VERSION 5.7 ;
  NOWIREEXTENSIONATPIN ON ;
  DIVIDERCHAR "/" ;
  BUSBITCHARS "[]" ;
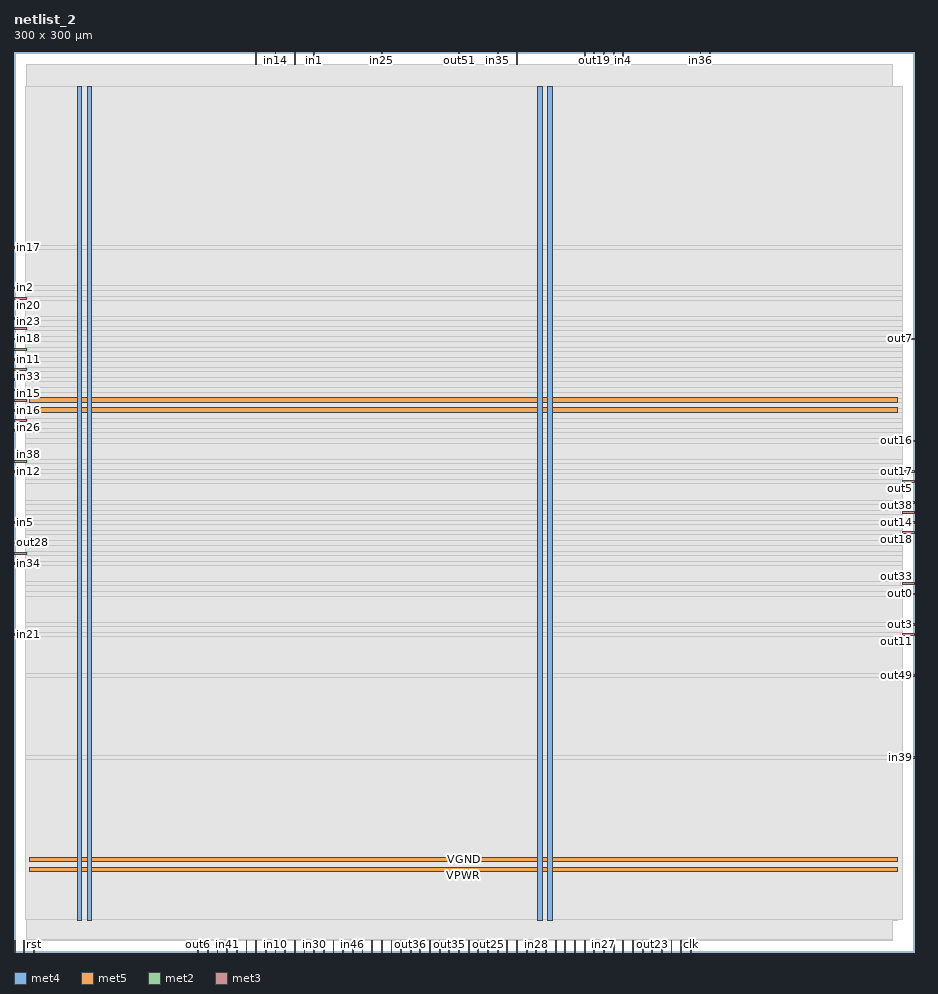
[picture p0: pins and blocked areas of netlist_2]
MACRO netlist_2
  CLASS BLOCK ;
  FOREIGN netlist_2 ;
  ORIGIN 0.000 0.000 ;
  SIZE 300.000 BY 300.000 ;
  PIN VGND
    DIRECTION INOUT ;
    USE GROUND ;
    PORT
      LAYER met4 ;
        RECT 24.340 10.640 25.940 288.560 ;
    END
    PORT
      LAYER met4 ;
        RECT 177.940 10.640 179.540 288.560 ;
    END
    PORT
      LAYER met5 ;
        RECT 5.280 30.030 294.640 31.630 ;
    END
    PORT
      LAYER met5 ;
        RECT 5.280 183.210 294.640 184.810 ;
    END
  END VGND
  PIN VPWR
    DIRECTION INOUT ;
    USE POWER ;
    PORT
      LAYER met4 ;
        RECT 21.040 10.640 22.640 288.560 ;
    END
    PORT
      LAYER met4 ;
        RECT 174.640 10.640 176.240 288.560 ;
    END
    PORT
      LAYER met5 ;
        RECT 5.280 26.730 294.640 28.330 ;
    END
    PORT
      LAYER met5 ;
        RECT 5.280 179.910 294.640 181.510 ;
    END
  END VPWR
  PIN clk
    DIRECTION INPUT ;
    USE SIGNAL ;
    ANTENNAGATEAREA 0.852000 ;
    ANTENNADIFFAREA 0.434700 ;
    PORT
      LAYER met2 ;
        RECT 225.490 0.000 225.770 4.000 ;
    END
  END clk
  PIN in0
    DIRECTION INPUT ;
    USE SIGNAL ;
    ANTENNAGATEAREA 0.213000 ;
    ANTENNADIFFAREA 0.434700 ;
    PORT
      LAYER met2 ;
        RECT 222.270 0.000 222.550 4.000 ;
    END
  END in0
  PIN in1
    DIRECTION INPUT ;
    USE SIGNAL ;
    ANTENNAGATEAREA 0.213000 ;
    ANTENNADIFFAREA 0.434700 ;
    PORT
      LAYER met2 ;
        RECT 99.910 296.000 100.190 300.000 ;
    END
  END in1
  PIN in10
    DIRECTION INPUT ;
    USE SIGNAL ;
    ANTENNAGATEAREA 0.196500 ;
    ANTENNADIFFAREA 0.434700 ;
    PORT
      LAYER met2 ;
        RECT 87.030 0.000 87.310 4.000 ;
    END
  END in10
  PIN in11
    DIRECTION INPUT ;
    USE SIGNAL ;
    ANTENNAGATEAREA 0.196500 ;
    ANTENNADIFFAREA 0.434700 ;
    PORT
      LAYER met3 ;
        RECT 0.000 197.240 4.000 197.840 ;
    END
  END in11
  PIN in12
    DIRECTION INPUT ;
    USE SIGNAL ;
    ANTENNAGATEAREA 0.196500 ;
    ANTENNADIFFAREA 0.434700 ;
    PORT
      LAYER met3 ;
        RECT 0.000 159.840 4.000 160.440 ;
    END
  END in12
  PIN in13
    DIRECTION INPUT ;
    USE SIGNAL ;
    ANTENNAGATEAREA 0.196500 ;
    ANTENNADIFFAREA 0.434700 ;
    PORT
      LAYER met2 ;
        RECT 93.470 296.000 93.750 300.000 ;
    END
  END in13
  PIN in14
    DIRECTION INPUT ;
    USE SIGNAL ;
    ANTENNAGATEAREA 0.213000 ;
    ANTENNADIFFAREA 0.434700 ;
    PORT
      LAYER met2 ;
        RECT 87.030 296.000 87.310 300.000 ;
    END
  END in14
  PIN in15
    DIRECTION INPUT ;
    USE SIGNAL ;
    ANTENNAGATEAREA 0.213000 ;
    ANTENNADIFFAREA 0.434700 ;
    PORT
      LAYER met3 ;
        RECT 0.000 183.640 4.000 184.240 ;
    END
  END in15
  PIN in16
    DIRECTION INPUT ;
    USE SIGNAL ;
    ANTENNAGATEAREA 0.126000 ;
    ANTENNADIFFAREA 0.434700 ;
    PORT
      LAYER met3 ;
        RECT 0.000 180.240 4.000 180.840 ;
    END
  END in16
  PIN in17
    DIRECTION INPUT ;
    USE SIGNAL ;
    ANTENNAGATEAREA 0.213000 ;
    ANTENNADIFFAREA 0.434700 ;
    PORT
      LAYER met3 ;
        RECT 0.000 234.640 4.000 235.240 ;
    END
  END in17
  PIN in18
    DIRECTION INPUT ;
    USE SIGNAL ;
    ANTENNAGATEAREA 0.196500 ;
    ANTENNADIFFAREA 0.434700 ;
    PORT
      LAYER met3 ;
        RECT 0.000 204.040 4.000 204.640 ;
    END
  END in18
  PIN in19
    DIRECTION INPUT ;
    USE SIGNAL ;
    ANTENNAGATEAREA 0.213000 ;
    ANTENNADIFFAREA 0.434700 ;
    PORT
      LAYER met2 ;
        RECT 215.830 0.000 216.110 4.000 ;
    END
  END in19
  PIN in2
    DIRECTION INPUT ;
    USE SIGNAL ;
    ANTENNAGATEAREA 0.213000 ;
    ANTENNADIFFAREA 0.434700 ;
    PORT
      LAYER met3 ;
        RECT 0.000 221.040 4.000 221.640 ;
    END
  END in2
  PIN in20
    DIRECTION INPUT ;
    USE SIGNAL ;
    ANTENNAGATEAREA 0.213000 ;
    ANTENNADIFFAREA 0.434700 ;
    PORT
      LAYER met3 ;
        RECT 0.000 217.640 4.000 218.240 ;
    END
  END in20
  PIN in21
    DIRECTION INPUT ;
    USE SIGNAL ;
    ANTENNAGATEAREA 0.196500 ;
    ANTENNADIFFAREA 0.434700 ;
    PORT
      LAYER met3 ;
        RECT 0.000 105.440 4.000 106.040 ;
    END
  END in21
  PIN in22
    DIRECTION INPUT ;
    USE SIGNAL ;
    ANTENNAGATEAREA 0.196500 ;
    ANTENNADIFFAREA 0.434700 ;
    PORT
      LAYER met2 ;
        RECT 67.710 0.000 67.990 4.000 ;
    END
  END in22
  PIN in23
    DIRECTION INPUT ;
    USE SIGNAL ;
    ANTENNAGATEAREA 0.196500 ;
    ANTENNADIFFAREA 0.434700 ;
    PORT
      LAYER met3 ;
        RECT 0.000 207.440 4.000 208.040 ;
    END
  END in23
  PIN in24
    DIRECTION INPUT ;
    USE SIGNAL ;
    ANTENNAGATEAREA 0.196500 ;
    ANTENNADIFFAREA 0.434700 ;
    PORT
      LAYER met2 ;
        RECT 93.470 0.000 93.750 4.000 ;
    END
  END in24
  PIN in25
    DIRECTION INPUT ;
    USE SIGNAL ;
    ANTENNAGATEAREA 0.196500 ;
    ANTENNADIFFAREA 0.434700 ;
    PORT
      LAYER met2 ;
        RECT 122.450 296.000 122.730 300.000 ;
    END
  END in25
  PIN in26
    DIRECTION INPUT ;
    USE SIGNAL ;
    ANTENNAGATEAREA 0.196500 ;
    ANTENNADIFFAREA 0.434700 ;
    PORT
      LAYER met3 ;
        RECT 0.000 176.840 4.000 177.440 ;
    END
  END in26
  PIN in27
    DIRECTION INPUT ;
    USE SIGNAL ;
    ANTENNAGATEAREA 0.196500 ;
    ANTENNADIFFAREA 0.434700 ;
    PORT
      LAYER met2 ;
        RECT 196.510 0.000 196.790 4.000 ;
    END
  END in27
  PIN in28
    DIRECTION INPUT ;
    USE SIGNAL ;
    ANTENNAGATEAREA 0.196500 ;
    ANTENNADIFFAREA 0.434700 ;
    PORT
      LAYER met2 ;
        RECT 173.970 0.000 174.250 4.000 ;
    END
  END in28
  PIN in29
    DIRECTION INPUT ;
    USE SIGNAL ;
    ANTENNAGATEAREA 0.196500 ;
    ANTENNADIFFAREA 0.434700 ;
    PORT
      LAYER met3 ;
        RECT 0.000 200.640 4.000 201.240 ;
    END
  END in29
  PIN in3
    DIRECTION INPUT ;
    USE SIGNAL ;
    ANTENNAGATEAREA 0.213000 ;
    ANTENNADIFFAREA 0.434700 ;
    PORT
      LAYER met3 ;
        RECT 0.000 210.840 4.000 211.440 ;
    END
  END in3
  PIN in30
    DIRECTION INPUT ;
    USE SIGNAL ;
    ANTENNAGATEAREA 0.196500 ;
    ANTENNADIFFAREA 0.434700 ;
    PORT
      LAYER met2 ;
        RECT 99.910 0.000 100.190 4.000 ;
    END
  END in30
  PIN in31
    DIRECTION INPUT ;
    USE SIGNAL ;
    ANTENNAGATEAREA 0.213000 ;
    ANTENNADIFFAREA 0.434700 ;
    PORT
      LAYER met2 ;
        RECT 90.250 0.000 90.530 4.000 ;
    END
  END in31
  PIN in32
    DIRECTION INPUT ;
    USE SIGNAL ;
    ANTENNAGATEAREA 0.213000 ;
    ANTENNADIFFAREA 0.434700 ;
    PORT
      LAYER met2 ;
        RECT 138.550 0.000 138.830 4.000 ;
    END
  END in32
  PIN in33
    DIRECTION INPUT ;
    USE SIGNAL ;
    ANTENNAGATEAREA 0.196500 ;
    ANTENNADIFFAREA 0.434700 ;
    PORT
      LAYER met3 ;
        RECT 0.000 193.840 4.000 194.440 ;
    END
  END in33
  PIN in34
    DIRECTION INPUT ;
    USE SIGNAL ;
    ANTENNAGATEAREA 0.196500 ;
    ANTENNADIFFAREA 0.434700 ;
    PORT
      LAYER met3 ;
        RECT 0.000 129.240 4.000 129.840 ;
    END
  END in34
  PIN in35
    DIRECTION INPUT ;
    USE SIGNAL ;
    ANTENNAGATEAREA 0.159000 ;
    ANTENNADIFFAREA 0.434700 ;
    PORT
      LAYER met2 ;
        RECT 161.090 296.000 161.370 300.000 ;
    END
  END in35
  PIN in36
    DIRECTION INPUT ;
    USE SIGNAL ;
    ANTENNAGATEAREA 0.196500 ;
    ANTENNADIFFAREA 0.434700 ;
    PORT
      LAYER met2 ;
        RECT 228.710 296.000 228.990 300.000 ;
    END
  END in36
  PIN in37
    DIRECTION INPUT ;
    USE SIGNAL ;
    ANTENNAGATEAREA 0.213000 ;
    ANTENNADIFFAREA 0.434700 ;
    PORT
      LAYER met2 ;
        RECT 83.810 0.000 84.090 4.000 ;
    END
  END in37
  PIN in38
    DIRECTION INPUT ;
    USE SIGNAL ;
    ANTENNAGATEAREA 0.196500 ;
    ANTENNADIFFAREA 0.434700 ;
    PORT
      LAYER met3 ;
        RECT 0.000 163.240 4.000 163.840 ;
    END
  END in38
  PIN in39
    DIRECTION INPUT ;
    USE SIGNAL ;
    ANTENNAGATEAREA 0.426000 ;
    ANTENNADIFFAREA 0.434700 ;
    PORT
      LAYER met3 ;
        RECT 296.000 64.640 300.000 65.240 ;
    END
  END in39
  PIN in4
    DIRECTION INPUT ;
    USE SIGNAL ;
    ANTENNAGATEAREA 0.159000 ;
    ANTENNADIFFAREA 0.434700 ;
    PORT
      LAYER met2 ;
        RECT 202.950 296.000 203.230 300.000 ;
    END
  END in4
  PIN in40
    DIRECTION INPUT ;
    USE SIGNAL ;
    ANTENNAGATEAREA 0.159000 ;
    ANTENNADIFFAREA 0.434700 ;
    PORT
      LAYER met2 ;
        RECT 167.530 0.000 167.810 4.000 ;
    END
  END in40
  PIN in41
    DIRECTION INPUT ;
    USE SIGNAL ;
    ANTENNAGATEAREA 0.196500 ;
    ANTENNADIFFAREA 0.434700 ;
    PORT
      LAYER met2 ;
        RECT 70.930 0.000 71.210 4.000 ;
    END
  END in41
  PIN in42
    DIRECTION INPUT ;
    USE SIGNAL ;
    ANTENNAGATEAREA 0.159000 ;
    ANTENNADIFFAREA 0.434700 ;
    PORT
      LAYER met2 ;
        RECT 109.570 0.000 109.850 4.000 ;
    END
  END in42
  PIN in43
    DIRECTION INPUT ;
    USE SIGNAL ;
    ANTENNAGATEAREA 0.196500 ;
    ANTENNADIFFAREA 0.434700 ;
    PORT
      LAYER met2 ;
        RECT 80.590 0.000 80.870 4.000 ;
    END
  END in43
  PIN in44
    DIRECTION INPUT ;
    USE SIGNAL ;
    ANTENNAGATEAREA 0.196500 ;
    ANTENNADIFFAREA 0.434700 ;
    PORT
      LAYER met2 ;
        RECT 119.230 0.000 119.510 4.000 ;
    END
  END in44
  PIN in45
    DIRECTION INPUT ;
    USE SIGNAL ;
    ANTENNAGATEAREA 0.196500 ;
    ANTENNADIFFAREA 0.434700 ;
    PORT
      LAYER met2 ;
        RECT 103.130 0.000 103.410 4.000 ;
    END
  END in45
  PIN in46
    DIRECTION INPUT ;
    USE SIGNAL ;
    ANTENNAGATEAREA 0.213000 ;
    ANTENNADIFFAREA 0.434700 ;
    PORT
      LAYER met2 ;
        RECT 112.790 0.000 113.070 4.000 ;
    END
  END in46
  PIN in47
    DIRECTION INPUT ;
    USE SIGNAL ;
    ANTENNAGATEAREA 0.213000 ;
    ANTENNADIFFAREA 0.434700 ;
    PORT
      LAYER met2 ;
        RECT 116.010 0.000 116.290 4.000 ;
    END
  END in47
  PIN in48
    DIRECTION INPUT ;
    USE SIGNAL ;
    ANTENNAGATEAREA 0.196500 ;
    ANTENNADIFFAREA 0.434700 ;
    PORT
      LAYER met2 ;
        RECT 77.370 0.000 77.650 4.000 ;
    END
  END in48
  PIN in49
    DIRECTION INPUT ;
    USE SIGNAL ;
    ANTENNAGATEAREA 0.159000 ;
    ANTENNADIFFAREA 0.434700 ;
    PORT
      LAYER met3 ;
        RECT 0.000 132.640 4.000 133.240 ;
    END
  END in49
  PIN in5
    DIRECTION INPUT ;
    USE SIGNAL ;
    ANTENNAGATEAREA 0.159000 ;
    ANTENNADIFFAREA 0.434700 ;
    PORT
      LAYER met3 ;
        RECT 0.000 142.840 4.000 143.440 ;
    END
  END in5
  PIN in50
    DIRECTION INPUT ;
    USE SIGNAL ;
    ANTENNAGATEAREA 0.196500 ;
    ANTENNADIFFAREA 0.434700 ;
    PORT
      LAYER met2 ;
        RECT 74.150 0.000 74.430 4.000 ;
    END
  END in50
  PIN in51
    DIRECTION INPUT ;
    USE SIGNAL ;
    ANTENNAGATEAREA 0.196500 ;
    ANTENNADIFFAREA 0.434700 ;
    PORT
      LAYER met2 ;
        RECT 106.350 0.000 106.630 4.000 ;
    END
  END in51
  PIN in6
    DIRECTION INPUT ;
    USE SIGNAL ;
    ANTENNAGATEAREA 0.159000 ;
    ANTENNADIFFAREA 0.434700 ;
    PORT
      LAYER met3 ;
        RECT 0.000 173.440 4.000 174.040 ;
    END
  END in6
  PIN in7
    DIRECTION INPUT ;
    USE SIGNAL ;
    ANTENNAGATEAREA 0.196500 ;
    ANTENNADIFFAREA 0.434700 ;
    PORT
      LAYER met2 ;
        RECT 80.590 296.000 80.870 300.000 ;
    END
  END in7
  PIN in8
    DIRECTION INPUT ;
    USE SIGNAL ;
    ANTENNAGATEAREA 0.159000 ;
    ANTENNADIFFAREA 0.434700 ;
    PORT
      LAYER met3 ;
        RECT 0.000 190.440 4.000 191.040 ;
    END
  END in8
  PIN in9
    DIRECTION INPUT ;
    USE SIGNAL ;
    ANTENNAGATEAREA 0.213000 ;
    ANTENNADIFFAREA 0.434700 ;
    PORT
      LAYER met3 ;
        RECT 0.000 187.040 4.000 187.640 ;
    END
  END in9
  PIN out0
    DIRECTION OUTPUT ;
    USE SIGNAL ;
    ANTENNADIFFAREA 0.445500 ;
    PORT
      LAYER met3 ;
        RECT 296.000 119.040 300.000 119.640 ;
    END
  END out0
  PIN out1
    DIRECTION OUTPUT ;
    USE SIGNAL ;
    ANTENNADIFFAREA 0.445500 ;
    PORT
      LAYER met2 ;
        RECT 202.950 0.000 203.230 4.000 ;
    END
  END out1
  PIN out10
    DIRECTION OUTPUT ;
    USE SIGNAL ;
    ANTENNADIFFAREA 0.445500 ;
    PORT
      LAYER met2 ;
        RECT 135.330 0.000 135.610 4.000 ;
    END
  END out10
  PIN out11
    DIRECTION OUTPUT ;
    USE SIGNAL ;
    ANTENNADIFFAREA 0.445500 ;
    PORT
      LAYER met3 ;
        RECT 296.000 105.440 300.000 106.040 ;
    END
  END out11
  PIN out12
    DIRECTION OUTPUT ;
    USE SIGNAL ;
    ANTENNADIFFAREA 0.445500 ;
    PORT
      LAYER met3 ;
        RECT 296.000 149.640 300.000 150.240 ;
    END
  END out12
  PIN out13
    DIRECTION OUTPUT ;
    USE SIGNAL ;
    ANTENNADIFFAREA 0.445500 ;
    PORT
      LAYER met2 ;
        RECT 141.770 0.000 142.050 4.000 ;
    END
  END out13
  PIN out14
    DIRECTION OUTPUT ;
    USE SIGNAL ;
    ANTENNADIFFAREA 0.445500 ;
    PORT
      LAYER met3 ;
        RECT 296.000 142.840 300.000 143.440 ;
    END
  END out14
  PIN out15
    DIRECTION OUTPUT ;
    USE SIGNAL ;
    ANTENNADIFFAREA 0.795200 ;
    PORT
      LAYER met2 ;
        RECT 231.930 296.000 232.210 300.000 ;
    END
  END out15
  PIN out16
    DIRECTION OUTPUT ;
    USE SIGNAL ;
    ANTENNADIFFAREA 0.445500 ;
    PORT
      LAYER met3 ;
        RECT 296.000 170.040 300.000 170.640 ;
    END
  END out16
  PIN out17
    DIRECTION OUTPUT ;
    USE SIGNAL ;
    ANTENNADIFFAREA 0.340600 ;
    PORT
      LAYER met3 ;
        RECT 296.000 159.840 300.000 160.440 ;
    END
  END out17
  PIN out18
    DIRECTION OUTPUT ;
    USE SIGNAL ;
    ANTENNADIFFAREA 0.340600 ;
    PORT
      LAYER met3 ;
        RECT 296.000 139.440 300.000 140.040 ;
    END
  END out18
  PIN out19
    DIRECTION OUTPUT ;
    USE SIGNAL ;
    ANTENNADIFFAREA 0.795200 ;
    PORT
      LAYER met2 ;
        RECT 193.290 296.000 193.570 300.000 ;
    END
  END out19
  PIN out2
    DIRECTION OUTPUT ;
    USE SIGNAL ;
    ANTENNADIFFAREA 0.795200 ;
    PORT
      LAYER met2 ;
        RECT 196.510 296.000 196.790 300.000 ;
    END
  END out2
  PIN out20
    DIRECTION OUTPUT ;
    USE SIGNAL ;
    ANTENNADIFFAREA 0.445500 ;
    PORT
      LAYER met2 ;
        RECT 125.670 0.000 125.950 4.000 ;
    END
  END out20
  PIN out21
    DIRECTION OUTPUT ;
    USE SIGNAL ;
    ANTENNADIFFAREA 0.445500 ;
    PORT
      LAYER met2 ;
        RECT 170.750 0.000 171.030 4.000 ;
    END
  END out21
  PIN out22
    DIRECTION OUTPUT ;
    USE SIGNAL ;
    PORT
      LAYER met2 ;
        RECT 0.090 0.000 0.370 4.000 ;
    END
  END out22
  PIN out23
    DIRECTION OUTPUT ;
    USE SIGNAL ;
    ANTENNADIFFAREA 0.445500 ;
    PORT
      LAYER met2 ;
        RECT 212.610 0.000 212.890 4.000 ;
    END
  END out23
  PIN out24
    DIRECTION OUTPUT ;
    USE SIGNAL ;
    ANTENNADIFFAREA 0.795200 ;
    PORT
      LAYER met2 ;
        RECT 199.730 296.000 200.010 300.000 ;
    END
  END out24
  PIN out25
    DIRECTION OUTPUT ;
    USE SIGNAL ;
    ANTENNADIFFAREA 0.445500 ;
    PORT
      LAYER met2 ;
        RECT 157.870 0.000 158.150 4.000 ;
    END
  END out25
  PIN out26
    DIRECTION OUTPUT ;
    USE SIGNAL ;
    ANTENNADIFFAREA 0.795200 ;
    PORT
      LAYER met2 ;
        RECT 190.070 296.000 190.350 300.000 ;
    END
  END out26
  PIN out27
    DIRECTION OUTPUT ;
    USE SIGNAL ;
    ANTENNADIFFAREA 0.340600 ;
    PORT
      LAYER met2 ;
        RECT 206.170 0.000 206.450 4.000 ;
    END
  END out27
  PIN out28
    DIRECTION OUTPUT ;
    USE SIGNAL ;
    ANTENNADIFFAREA 0.445500 ;
    PORT
      LAYER met3 ;
        RECT 0.000 136.040 4.000 136.640 ;
    END
  END out28
  PIN out29
    DIRECTION OUTPUT ;
    USE SIGNAL ;
    ANTENNADIFFAREA 0.445500 ;
    PORT
      LAYER met2 ;
        RECT 64.490 0.000 64.770 4.000 ;
    END
  END out29
  PIN out3
    DIRECTION OUTPUT ;
    USE SIGNAL ;
    ANTENNADIFFAREA 0.445500 ;
    PORT
      LAYER met3 ;
        RECT 296.000 108.840 300.000 109.440 ;
    END
  END out3
  PIN out30
    DIRECTION OUTPUT ;
    USE SIGNAL ;
    ANTENNADIFFAREA 0.445500 ;
    PORT
      LAYER met2 ;
        RECT 96.690 0.000 96.970 4.000 ;
    END
  END out30
  PIN out31
    DIRECTION OUTPUT ;
    USE SIGNAL ;
    ANTENNADIFFAREA 0.445500 ;
    PORT
      LAYER met2 ;
        RECT 148.210 0.000 148.490 4.000 ;
    END
  END out31
  PIN out32
    DIRECTION OUTPUT ;
    USE SIGNAL ;
    ANTENNADIFFAREA 0.445500 ;
    PORT
      LAYER met2 ;
        RECT 183.630 0.000 183.910 4.000 ;
    END
  END out32
  PIN out33
    DIRECTION OUTPUT ;
    USE SIGNAL ;
    ANTENNADIFFAREA 0.445500 ;
    PORT
      LAYER met3 ;
        RECT 296.000 122.440 300.000 123.040 ;
    END
  END out33
  PIN out34
    DIRECTION OUTPUT ;
    USE SIGNAL ;
    ANTENNADIFFAREA 0.445500 ;
    PORT
      LAYER met2 ;
        RECT 128.890 0.000 129.170 4.000 ;
    END
  END out34
  PIN out35
    DIRECTION OUTPUT ;
    USE SIGNAL ;
    ANTENNADIFFAREA 0.445500 ;
    PORT
      LAYER met2 ;
        RECT 144.990 0.000 145.270 4.000 ;
    END
  END out35
  PIN out36
    DIRECTION OUTPUT ;
    USE SIGNAL ;
    ANTENNADIFFAREA 0.445500 ;
    PORT
      LAYER met2 ;
        RECT 132.110 0.000 132.390 4.000 ;
    END
  END out36
  PIN out37
    DIRECTION OUTPUT ;
    USE SIGNAL ;
    ANTENNADIFFAREA 0.445500 ;
    PORT
      LAYER met2 ;
        RECT 180.410 0.000 180.690 4.000 ;
    END
  END out37
  PIN out38
    DIRECTION OUTPUT ;
    USE SIGNAL ;
    ANTENNADIFFAREA 0.445500 ;
    PORT
      LAYER met3 ;
        RECT 296.000 146.240 300.000 146.840 ;
    END
  END out38
  PIN out39
    DIRECTION OUTPUT ;
    USE SIGNAL ;
    ANTENNADIFFAREA 0.445500 ;
    PORT
      LAYER met2 ;
        RECT 193.290 0.000 193.570 4.000 ;
    END
  END out39
  PIN out4
    DIRECTION OUTPUT ;
    USE SIGNAL ;
    ANTENNADIFFAREA 0.445500 ;
    PORT
      LAYER met2 ;
        RECT 154.650 0.000 154.930 4.000 ;
    END
  END out4
  PIN out40
    DIRECTION OUTPUT ;
    USE SIGNAL ;
    ANTENNADIFFAREA 0.445500 ;
    PORT
      LAYER met2 ;
        RECT 186.850 0.000 187.130 4.000 ;
    END
  END out40
  PIN out41
    DIRECTION OUTPUT ;
    USE SIGNAL ;
    ANTENNADIFFAREA 0.445500 ;
    PORT
      LAYER met2 ;
        RECT 151.430 0.000 151.710 4.000 ;
    END
  END out41
  PIN out42
    DIRECTION OUTPUT ;
    USE SIGNAL ;
    ANTENNADIFFAREA 0.340600 ;
    PORT
      LAYER met2 ;
        RECT 167.530 296.000 167.810 300.000 ;
    END
  END out42
  PIN out43
    DIRECTION OUTPUT ;
    USE SIGNAL ;
    ANTENNADIFFAREA 0.445500 ;
    PORT
      LAYER met2 ;
        RECT 122.450 0.000 122.730 4.000 ;
    END
  END out43
  PIN out44
    DIRECTION OUTPUT ;
    USE SIGNAL ;
    ANTENNADIFFAREA 0.445500 ;
    PORT
      LAYER met2 ;
        RECT 177.190 0.000 177.470 4.000 ;
    END
  END out44
  PIN out45
    DIRECTION OUTPUT ;
    USE SIGNAL ;
    PORT
      LAYER met2 ;
        RECT 3.310 0.000 3.590 4.000 ;
    END
  END out45
  PIN out46
    DIRECTION OUTPUT ;
    USE SIGNAL ;
    ANTENNADIFFAREA 0.445500 ;
    PORT
      LAYER met2 ;
        RECT 164.310 0.000 164.590 4.000 ;
    END
  END out46
  PIN out47
    DIRECTION OUTPUT ;
    USE SIGNAL ;
    ANTENNADIFFAREA 0.445500 ;
    PORT
      LAYER met2 ;
        RECT 219.050 0.000 219.330 4.000 ;
    END
  END out47
  PIN out48
    DIRECTION OUTPUT ;
    USE SIGNAL ;
    ANTENNADIFFAREA 0.340600 ;
    PORT
      LAYER met2 ;
        RECT 190.070 0.000 190.350 4.000 ;
    END
  END out48
  PIN out49
    DIRECTION OUTPUT ;
    USE SIGNAL ;
    ANTENNADIFFAREA 0.445500 ;
    PORT
      LAYER met3 ;
        RECT 296.000 91.840 300.000 92.440 ;
    END
  END out49
  PIN out5
    DIRECTION OUTPUT ;
    USE SIGNAL ;
    ANTENNADIFFAREA 0.445500 ;
    PORT
      LAYER met3 ;
        RECT 296.000 156.440 300.000 157.040 ;
    END
  END out5
  PIN out50
    DIRECTION OUTPUT ;
    USE SIGNAL ;
    ANTENNADIFFAREA 0.340600 ;
    PORT
      LAYER met2 ;
        RECT 161.090 0.000 161.370 4.000 ;
    END
  END out50
  PIN out51
    DIRECTION OUTPUT ;
    USE SIGNAL ;
    ANTENNADIFFAREA 0.340600 ;
    PORT
      LAYER met2 ;
        RECT 148.210 296.000 148.490 300.000 ;
    END
  END out51
  PIN out6
    DIRECTION OUTPUT ;
    USE SIGNAL ;
    ANTENNADIFFAREA 0.445500 ;
    PORT
      LAYER met2 ;
        RECT 61.270 0.000 61.550 4.000 ;
    END
  END out6
  PIN out7
    DIRECTION OUTPUT ;
    USE SIGNAL ;
    ANTENNADIFFAREA 0.445500 ;
    PORT
      LAYER met3 ;
        RECT 296.000 204.040 300.000 204.640 ;
    END
  END out7
  PIN out8
    DIRECTION OUTPUT ;
    USE SIGNAL ;
    ANTENNADIFFAREA 0.445500 ;
    PORT
      LAYER met2 ;
        RECT 199.730 0.000 200.010 4.000 ;
    END
  END out8
  PIN out9
    DIRECTION OUTPUT ;
    USE SIGNAL ;
    ANTENNADIFFAREA 0.445500 ;
    PORT
      LAYER met2 ;
        RECT 209.390 0.000 209.670 4.000 ;
    END
  END out9
  PIN rst
    DIRECTION INPUT ;
    USE SIGNAL ;
    PORT
      LAYER met2 ;
        RECT 6.530 0.000 6.810 4.000 ;
    END
  END rst
  OBS
      LAYER li1 ;
        RECT 5.520 10.795 294.400 288.405 ;
      LAYER met1 ;
        RECT 4.210 10.640 294.400 288.560 ;
      LAYER met2 ;
        RECT 4.230 295.720 80.310 296.000 ;
        RECT 81.150 295.720 86.750 296.000 ;
        RECT 87.590 295.720 93.190 296.000 ;
        RECT 94.030 295.720 99.630 296.000 ;
        RECT 100.470 295.720 122.170 296.000 ;
        RECT 123.010 295.720 147.930 296.000 ;
        RECT 148.770 295.720 160.810 296.000 ;
        RECT 161.650 295.720 167.250 296.000 ;
        RECT 168.090 295.720 189.790 296.000 ;
        RECT 190.630 295.720 193.010 296.000 ;
        RECT 193.850 295.720 196.230 296.000 ;
        RECT 197.070 295.720 199.450 296.000 ;
        RECT 200.290 295.720 202.670 296.000 ;
        RECT 203.510 295.720 228.430 296.000 ;
        RECT 229.270 295.720 231.650 296.000 ;
        RECT 232.490 295.720 292.930 296.000 ;
        RECT 4.230 4.280 292.930 295.720 ;
        RECT 4.230 4.000 6.250 4.280 ;
        RECT 7.090 4.000 60.990 4.280 ;
        RECT 61.830 4.000 64.210 4.280 ;
        RECT 65.050 4.000 67.430 4.280 ;
        RECT 68.270 4.000 70.650 4.280 ;
        RECT 71.490 4.000 73.870 4.280 ;
        RECT 74.710 4.000 77.090 4.280 ;
        RECT 77.930 4.000 80.310 4.280 ;
        RECT 81.150 4.000 83.530 4.280 ;
        RECT 84.370 4.000 86.750 4.280 ;
        RECT 87.590 4.000 89.970 4.280 ;
        RECT 90.810 4.000 93.190 4.280 ;
        RECT 94.030 4.000 96.410 4.280 ;
        RECT 97.250 4.000 99.630 4.280 ;
        RECT 100.470 4.000 102.850 4.280 ;
        RECT 103.690 4.000 106.070 4.280 ;
        RECT 106.910 4.000 109.290 4.280 ;
        RECT 110.130 4.000 112.510 4.280 ;
        RECT 113.350 4.000 115.730 4.280 ;
        RECT 116.570 4.000 118.950 4.280 ;
        RECT 119.790 4.000 122.170 4.280 ;
        RECT 123.010 4.000 125.390 4.280 ;
        RECT 126.230 4.000 128.610 4.280 ;
        RECT 129.450 4.000 131.830 4.280 ;
        RECT 132.670 4.000 135.050 4.280 ;
        RECT 135.890 4.000 138.270 4.280 ;
        RECT 139.110 4.000 141.490 4.280 ;
        RECT 142.330 4.000 144.710 4.280 ;
        RECT 145.550 4.000 147.930 4.280 ;
        RECT 148.770 4.000 151.150 4.280 ;
        RECT 151.990 4.000 154.370 4.280 ;
        RECT 155.210 4.000 157.590 4.280 ;
        RECT 158.430 4.000 160.810 4.280 ;
        RECT 161.650 4.000 164.030 4.280 ;
        RECT 164.870 4.000 167.250 4.280 ;
        RECT 168.090 4.000 170.470 4.280 ;
        RECT 171.310 4.000 173.690 4.280 ;
        RECT 174.530 4.000 176.910 4.280 ;
        RECT 177.750 4.000 180.130 4.280 ;
        RECT 180.970 4.000 183.350 4.280 ;
        RECT 184.190 4.000 186.570 4.280 ;
        RECT 187.410 4.000 189.790 4.280 ;
        RECT 190.630 4.000 193.010 4.280 ;
        RECT 193.850 4.000 196.230 4.280 ;
        RECT 197.070 4.000 199.450 4.280 ;
        RECT 200.290 4.000 202.670 4.280 ;
        RECT 203.510 4.000 205.890 4.280 ;
        RECT 206.730 4.000 209.110 4.280 ;
        RECT 209.950 4.000 212.330 4.280 ;
        RECT 213.170 4.000 215.550 4.280 ;
        RECT 216.390 4.000 218.770 4.280 ;
        RECT 219.610 4.000 221.990 4.280 ;
        RECT 222.830 4.000 225.210 4.280 ;
        RECT 226.050 4.000 292.930 4.280 ;
      LAYER met3 ;
        RECT 3.990 235.640 296.000 288.485 ;
        RECT 4.400 234.240 296.000 235.640 ;
        RECT 3.990 222.040 296.000 234.240 ;
        RECT 4.400 220.640 296.000 222.040 ;
        RECT 3.990 218.640 296.000 220.640 ;
        RECT 4.400 217.240 296.000 218.640 ;
        RECT 3.990 211.840 296.000 217.240 ;
        RECT 4.400 210.440 296.000 211.840 ;
        RECT 3.990 208.440 296.000 210.440 ;
        RECT 4.400 207.040 296.000 208.440 ;
        RECT 3.990 205.040 296.000 207.040 ;
        RECT 4.400 203.640 295.600 205.040 ;
        RECT 3.990 201.640 296.000 203.640 ;
        RECT 4.400 200.240 296.000 201.640 ;
        RECT 3.990 198.240 296.000 200.240 ;
        RECT 4.400 196.840 296.000 198.240 ;
        RECT 3.990 194.840 296.000 196.840 ;
        RECT 4.400 193.440 296.000 194.840 ;
        RECT 3.990 191.440 296.000 193.440 ;
        RECT 4.400 190.040 296.000 191.440 ;
        RECT 3.990 188.040 296.000 190.040 ;
        RECT 4.400 186.640 296.000 188.040 ;
        RECT 3.990 184.640 296.000 186.640 ;
        RECT 4.400 183.240 296.000 184.640 ;
        RECT 3.990 181.240 296.000 183.240 ;
        RECT 4.400 179.840 296.000 181.240 ;
        RECT 3.990 177.840 296.000 179.840 ;
        RECT 4.400 176.440 296.000 177.840 ;
        RECT 3.990 174.440 296.000 176.440 ;
        RECT 4.400 173.040 296.000 174.440 ;
        RECT 3.990 171.040 296.000 173.040 ;
        RECT 3.990 169.640 295.600 171.040 ;
        RECT 3.990 164.240 296.000 169.640 ;
        RECT 4.400 162.840 296.000 164.240 ;
        RECT 3.990 160.840 296.000 162.840 ;
        RECT 4.400 159.440 295.600 160.840 ;
        RECT 3.990 157.440 296.000 159.440 ;
        RECT 3.990 156.040 295.600 157.440 ;
        RECT 3.990 150.640 296.000 156.040 ;
        RECT 3.990 149.240 295.600 150.640 ;
        RECT 3.990 147.240 296.000 149.240 ;
        RECT 3.990 145.840 295.600 147.240 ;
        RECT 3.990 143.840 296.000 145.840 ;
        RECT 4.400 142.440 295.600 143.840 ;
        RECT 3.990 140.440 296.000 142.440 ;
        RECT 3.990 139.040 295.600 140.440 ;
        RECT 3.990 137.040 296.000 139.040 ;
        RECT 4.400 135.640 296.000 137.040 ;
        RECT 3.990 133.640 296.000 135.640 ;
        RECT 4.400 132.240 296.000 133.640 ;
        RECT 3.990 130.240 296.000 132.240 ;
        RECT 4.400 128.840 296.000 130.240 ;
        RECT 3.990 123.440 296.000 128.840 ;
        RECT 3.990 122.040 295.600 123.440 ;
        RECT 3.990 120.040 296.000 122.040 ;
        RECT 3.990 118.640 295.600 120.040 ;
        RECT 3.990 109.840 296.000 118.640 ;
        RECT 3.990 108.440 295.600 109.840 ;
        RECT 3.990 106.440 296.000 108.440 ;
        RECT 4.400 105.040 295.600 106.440 ;
        RECT 3.990 92.840 296.000 105.040 ;
        RECT 3.990 91.440 295.600 92.840 ;
        RECT 3.990 65.640 296.000 91.440 ;
        RECT 3.990 64.240 295.600 65.640 ;
        RECT 3.990 10.715 296.000 64.240 ;
  END
END netlist_2
END LIBRARY

